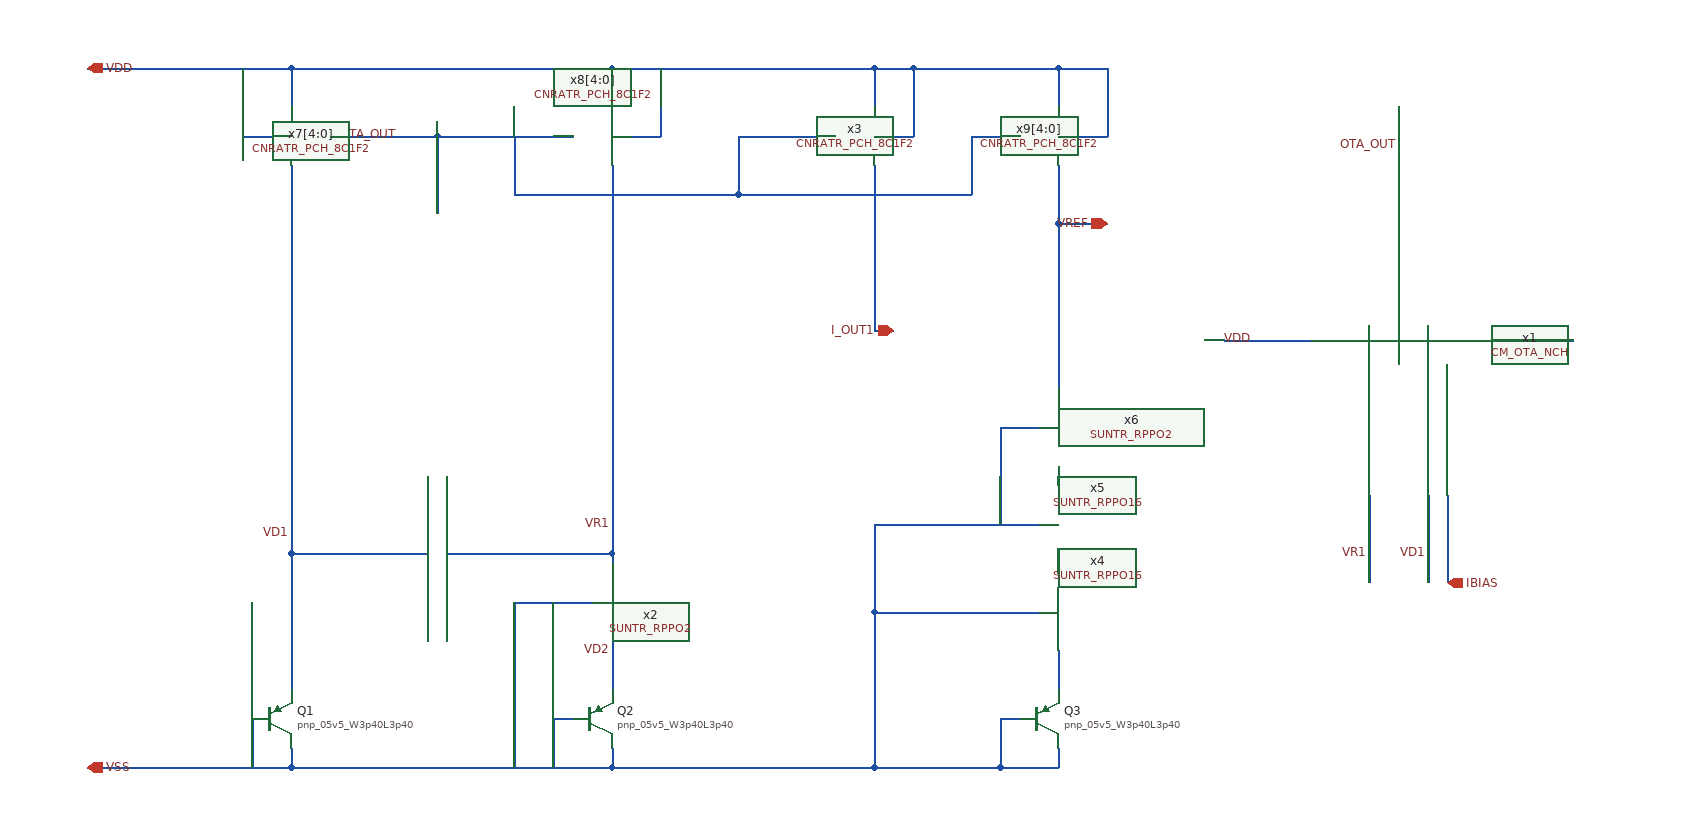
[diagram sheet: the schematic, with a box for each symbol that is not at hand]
v {xschem version=3.4.4 file_version=1.2
}
G {}
K {}
V {}
S {}
E {}
N 880 -120 880 -20 {
lab=OTA_OUT}
N 700 120 790 120 {
lab=VDD}
N 970 120 1060 120 {
lab=VSS}
N 850 280 850 370 {
lab=VR1}
N 910 280 910 370 {
lab=VD1}
N 930 280 930 370 {
lab=IBIAS}
N -110 -90 30 -90 {
lab=OTA_OUT}
N -220 -90 -110 -90 {
lab=OTA_OUT}
N -240 340 -140 340 {
lab=VD1}
N -260 -60 -260 340 {
lab=VD1}
N -260 340 -240 340 {
lab=VD1}
N -80 340 70 340 {
lab=VR1}
N -260 -160 -260 -120 {
lab=VDD}
N -260 -160 70 -160 {
lab=VDD}
N 70 -160 70 -120 {
lab=VDD}
N 340 -160 340 -120 {
lab=VDD}
N 70 -160 340 -160 {
lab=VDD}
N -30 -90 -30 -30 {
lab=OTA_OUT}
N -30 -30 200 -30 {
lab=OTA_OUT}
N 200 -90 200 -30 {
lab=OTA_OUT}
N 200 -90 300 -90 {
lab=OTA_OUT}
N -410 -160 -260 -160 {
lab=VDD}
N -470 -160 -410 -160 {
lab=VDD}
N -470 560 -260 560 {
lab=VSS}
N -260 560 70 560 {
lab=VSS}
N -310 -90 -260 -90 {
lab=VDD}
N -310 -160 -310 -90 {
lab=VDD}
N 70 -90 120 -90 {
lab=VDD}
N 120 -160 120 -90 {
lab=VDD}
N 340 -90 380 -90 {
lab=VDD}
N 380 -160 380 -90 {
lab=VDD}
N 340 -160 380 -160 {
lab=VDD}
N -120 260 -120 340 {
lab=VD1}
N -140 340 -120 340 {
lab=VD1}
N -100 260 -100 340 {
lab=VR1}
N -100 340 -80 340 {
lab=VR1}
N -110 -90 -110 -10 {
lab=OTA_OUT}
N 70 210 70 340 {
lab=VR1}
N 70 -60 70 210 {
lab=VR1}
N -260 340 -260 410 {
lab=VD1}
N 70 450 70 470 {
lab=VD2}
N 70 470 70 480 {
lab=VD2}
N -260 410 -260 450 {
lab=VD1}
N 70 540 70 560 {
lab=VSS}
N 10 510 30 510 {
lab=VSS}
N 10 510 10 560 {
lab=VSS}
N -260 540 -260 560 {
lab=VSS}
N -260 450 -260 480 {
lab=VD1}
N -300 510 -300 560 {
lab=VSS}
N 380 -160 530 -160 {
lab=VDD}
N 530 -160 530 -120 {
lab=VDD}
N 200 -30 440 -30 {
lab=OTA_OUT}
N 440 -90 440 -30 {
lab=OTA_OUT}
N 440 -90 490 -90 {
lab=OTA_OUT}
N 530 -50 530 0 {
lab=VREF}
N 530 0 580 0 {
lab=VREF}
N 530 -90 580 -90 {
lab=VDD}
N 580 -160 580 -90 {
lab=VDD}
N 530 -160 580 -160 {
lab=VDD}
N 530 -60 530 -50 {
lab=VREF}
N 340 -60 340 -20 {
lab=I_OUT1}
N 340 -20 340 -10 {
lab=I_OUT1}
N 340 -10 340 -0 {
lab=I_OUT1}
N 340 0 340 10 {
lab=I_OUT1}
N 340 10 340 20 {
lab=I_OUT1}
N 340 20 340 30 {
lab=I_OUT1}
N 340 30 340 40 {
lab=I_OUT1}
N 340 40 340 50 {
lab=I_OUT1}
N 340 50 340 60 {
lab=I_OUT1}
N 340 60 340 70 {
lab=I_OUT1}
N 340 70 340 80 {
lab=I_OUT1}
N 340 80 340 90 {
lab=I_OUT1}
N 340 90 340 100 {
lab=I_OUT1}
N 340 100 340 110 {
lab=I_OUT1}
N 340 110 360 110 {
lab=I_OUT1}
N 530 470 530 480 {
lab=#net1}
N 470 510 490 510 {
lab=VSS}
N 470 510 470 530 {
lab=VSS}
N 470 530 470 540 {
lab=VSS}
N 470 540 470 550 {
lab=VSS}
N 470 550 470 560 {
lab=VSS}
N 470 560 530 560 {
lab=VSS}
N 530 540 530 560 {
lab=VSS}
N 400 560 470 560 {
lab=VSS}
N 390 560 400 560 {
lab=VSS}
N 380 560 390 560 {
lab=VSS}
N 370 560 380 560 {
lab=VSS}
N 360 560 370 560 {
lab=VSS}
N 350 560 360 560 {
lab=VSS}
N 340 560 350 560 {
lab=VSS}
N 330 560 340 560 {
lab=VSS}
N 320 560 330 560 {
lab=VSS}
N 310 560 320 560 {
lab=VSS}
N 300 560 310 560 {
lab=VSS}
N 290 560 300 560 {
lab=VSS}
N 280 560 290 560 {
lab=VSS}
N 270 560 280 560 {
lab=VSS}
N 260 560 270 560 {
lab=VSS}
N 250 560 260 560 {
lab=VSS}
N 240 560 250 560 {
lab=VSS}
N 220 560 240 560 {
lab=VSS}
N 210 560 220 560 {
lab=VSS}
N 200 560 210 560 {
lab=VSS}
N 190 560 200 560 {
lab=VSS}
N 180 560 190 560 {
lab=VSS}
N 170 560 180 560 {
lab=VSS}
N 160 560 170 560 {
lab=VSS}
N 150 560 160 560 {
lab=VSS}
N 140 560 150 560 {
lab=VSS}
N 130 560 140 560 {
lab=VSS}
N 120 560 130 560 {
lab=VSS}
N 110 560 120 560 {
lab=VSS}
N 100 560 110 560 {
lab=VSS}
N 90 560 100 560 {
lab=VSS}
N 80 560 90 560 {
lab=VSS}
N 70 560 80 560 {
lab=VSS}
N 70 340 70 350 {
lab=VR1}
N 70 440 70 450 {
lab=VD2}
N 70 430 70 440 {
lab=VD2}
N -30 390 50 390 {
lab=VSS}
N -30 390 -30 560 {
lab=VSS}
N 530 440 530 470 {
lab=#net1}
N 340 400 510 400 {
lab=VSS}
N 340 400 340 560 {
lab=VSS}
N 530 350 530 360 {
lab=#net2}
N 340 310 510 310 {
lab=VSS}
N 340 310 340 400 {
lab=VSS}
N 530 -0 530 70 {
lab=VREF}
N 470 210 470 310 {
lab=VSS}
N 530 70 530 90 {
lab=VREF}
N 530 250 530 270 {
lab=#net3}
N 470 210 510 210 {
lab=VSS}
N 530 90 530 150 {
lab=VREF}
N 530 150 530 170 {
lab=VREF}
C {devices/iopin.sym} -470 -160 0 1 {name=p1 lab=VDD}
C {devices/iopin.sym} -470 560 0 1 {name=p4 lab=VSS}
C {devices/lab_wire.sym} 1040 120 0 0 {name=p6 sig_type=std_logic lab=VSS}
C {devices/lab_wire.sym} 850 340 1 0 {name=p13 sig_type=std_logic lab=VR1}
C {devices/lab_wire.sym} 910 340 1 0 {name=p14 sig_type=std_logic lab=VD1}
C {devices/lab_wire.sym} 730 120 0 0 {name=p15 sig_type=std_logic lab=VDD}
C {devices/lab_wire.sym} 880 -80 0 0 {name=p16 sig_type=std_logic lab=OTA_OUT}
C {devices/iopin.sym} 360 110 0 0 {name=p9 lab=I_OUT1}
C {devices/iopin.sym} 580 0 0 0 {name=p10 lab=VREF}
C {devices/lab_wire.sym} -260 320 0 0 {name=p2 sig_type=std_logic lab=VD1}
C {devices/lab_wire.sym} 70 310 0 0 {name=p3 sig_type=std_logic lab=VR1}
C {devices/lab_wire.sym} 70 440 0 0 {name=p5 sig_type=std_logic lab=VD2}
C {devices/lab_wire.sym} -150 -90 0 0 {name=p8 sig_type=std_logic lab=OTA_OUT}
C {CNR_ATR_SKY130NM/CNR_ATR_SKY130NM/CNRATR_PCH_8C1F2.sym} 300 -90 0 0 {name=x3}
C {CNR_ATR_SKY130NM/CNR_ATR_SKY130NM/CNRATR_PCH_8C1F2.sym} 30 -90 0 0 {name=x8[4:0]}
C {CNR_ATR_SKY130NM/CNR_ATR_SKY130NM/CNRATR_PCH_8C1F2.sym} -220 -90 0 1 {name=x7[4:0]}
C {sky130_fd_pr/pnp_05v5.sym} -280 510 0 0 {name=Q1
model=pnp_05v5_W3p40L3p40
m=1
spiceprefix=X
}
C {sky130_fd_pr/pnp_05v5.sym} 50 510 0 0 {name=Q2
model=pnp_05v5_W3p40L3p40
m=5
spiceprefix=X
}
C {CNR_ATR_SKY130NM/CNR_ATR_SKY130NM/CNRATR_PCH_8C1F2.sym} 490 -90 0 0 {name=x9[4:0]}
C {CNR_GR03_SKY130NM/CM_OTA_NCH.sym} 880 90 3 0 {name=x1}
C {sky130_fd_pr/pnp_05v5.sym} 510 510 0 0 {name=Q3
model=pnp_05v5_W3p40L3p40
m=5
spiceprefix=X
}
C {SUN_TR_SKY130NM/SUNTR_RPPO2.sym} 70 350 1 0 {name=x2 }
C {SUN_TR_SKY130NM/SUNTR_RPPO16.sym} 530 360 1 0 {name=x4 }
C {SUN_TR_SKY130NM/SUNTR_RPPO16.sym} 530 270 1 0 {name=x5 }
C {SUN_TR_SKY130NM/SUNTR_RPPO2.sym} 530 170 1 0 {name=x6 }
C {devices/iopin.sym} 930 370 3 1 {name=p7 lab=IBIAS}
